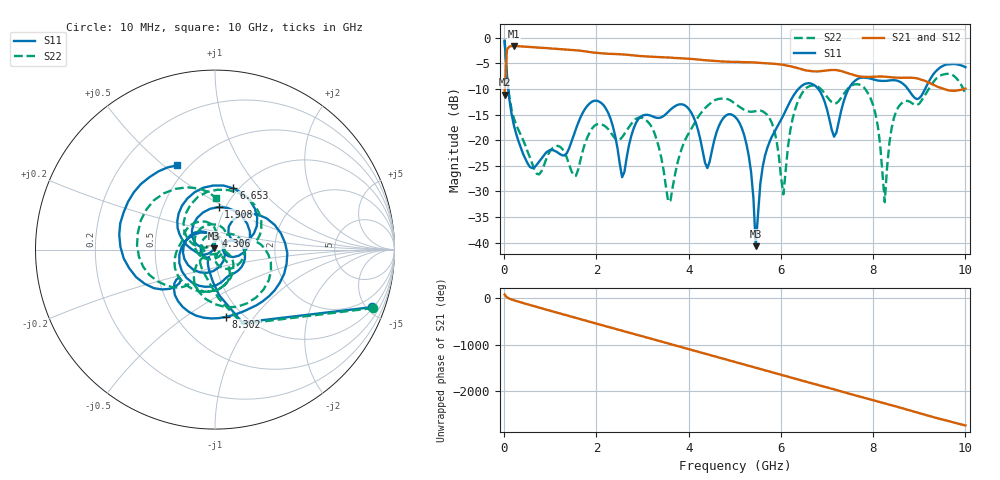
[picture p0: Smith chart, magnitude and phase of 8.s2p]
!Agilent Technologies,N5230C,MY49000813,A.09.42.22
!Agilent N5230C: A.09.42.22
!Date: Friday, August 21, 2026 19:39:36
!Correction: S11(Full 2 Port(1,2))
!S21(Full 2 Port(1,2))
!S12(Full 2 Port(1,2))
!S22(Full 2 Port(1,2))
!S2P File: Measurements: S11, S21, S12, S22:
# Hz S  dB  R 50
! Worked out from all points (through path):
!   201 points, 10 MHz to 10 GHz, reference 50 ohm
!   highest |S21| = -1.63 dB at 209.8 MHz (marker M1); lowest = -11.1 dB at 10 MHz (marker M2)
!   lowest |S11| = -40.7 dB at 5.455 GHz (marker M3), VSWR 1.02, Z = 49.4 + j0.718 ohm
!   |S11| at or under -10 dB: 89.87 MHz to 6.383 GHz (6.293 GHz wide, 194 % of centre); 6.809 GHz to 7.469 GHz (659.8 MHz wide, 9.24 % of centre); 8.751 GHz to 9.126 GHz (375.2 MHz wide, 4.2 % of centre)
!   |S22| runs from -32.1 to -0.5 dB; largest |S21 - S12| = 0.0067
!   S11 on the Smith chart (normalised r, x): 10 MHz: 1.08, -5.45; 1.908 GHz: 0.93, +0.47; 4.306 GHz: 0.99, +0.16; 6.653 GHz: 0.95, +0.74; 8.302 GHz: 0.84, -0.73; 10 GHz: 0.43, +0.55
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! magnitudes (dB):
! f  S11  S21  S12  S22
! 10 MHz  -0.6  -11.1  -11.3  -0.5
! 209.8 MHz  -17.1  -1.6  -1.6  -15.7
! 609.4 MHz  -25.5  -1.8  -1.9  -24.6
! 1.708 GHz  -14.6  -2.6  -2.6  -22.0
! 1.908 GHz  -12.5  -2.9  -2.9  -17.7
! 2.557 GHz  -27.2  -3.3  -3.3  -19.4
! 3.357 GHz  -15.7  -3.8  -3.8  -21.5
! 3.606 GHz  -14.1  -3.9  -3.9  -31.8
! 4.306 GHz  -22.2  -4.4  -4.4  -14.3
! 5.005 GHz  -15.4  -4.7  -4.7  -12.9
! 5.305 GHz  -23.1  -4.8  -4.8  -14.4
! 5.455 GHz  -40.7  -4.9  -4.9  -14.3
! 5.654 GHz  -23.1  -5.0  -5.0  -14.7
! 6.054 GHz  -15.1  -5.3  -5.3  -30.6
! 6.653 GHz  -9.0  -6.5  -6.5  -9.4
! 6.703 GHz  -9.1  -6.6  -6.6  -9.3
! 7.153 GHz  -19.3  -6.3  -6.3  -12.9
! 7.802 GHz  -7.8  -7.7  -7.7  -9.7
! 8.252 GHz  -8.4  -7.6  -7.6  -32.1
! 8.302 GHz  -8.4  -7.6  -7.7  -25.4
! 8.352 GHz  -8.3  -7.7  -7.7  -20.6
! 10 GHz  -5.8  -9.9  -9.9  -10.9
